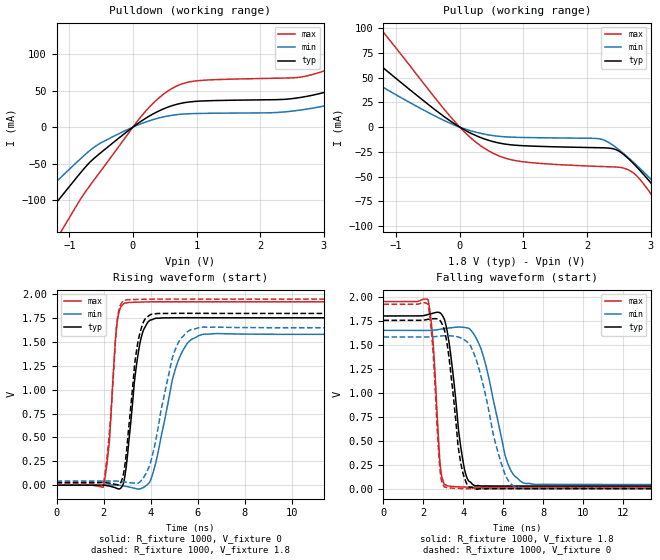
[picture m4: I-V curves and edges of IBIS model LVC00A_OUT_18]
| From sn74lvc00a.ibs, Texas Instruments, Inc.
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[Model]   LVC00A_OUT_18
Model_type  Output
Vref =   0
Rref =   1000
Cref =   30p
Vmeas =   0.9
| variable   typ   min   max
C_comp   6.70pF   4.46pF   9.98pF
| C_pullup   5.89pF   4.46pF   6.78pF
| C_pulldown   7.50pF   4.66pF   9.98pF
[Temperature Range]   40   100   -40
| Ambient temperature   25   85   -40
[Voltage range]   1.8   1.65   1.95
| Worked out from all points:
|   slope of the pulldown table from 0 to 0.27 V, typ, clamps not added: 17.1 ohm
|   slope of the pullup table from 0 to 0.27 V, typ, clamps not added: 29.9 ohm
|   rising waveform, R_fixture 1000, V_fixture 0: 20-80 % time 453ps typ, 823ps min, 292ps max; typ from 0 V to 1.75 V
|   falling waveform, R_fixture 1000, V_fixture 1.8: 20-80 % time 574ps typ, 1ns min, 320ps max; typ from 1.8 V to 0.027 V
|   rising waveform, R_fixture 1000, V_fixture 1.8: 20-80 % time 437ps typ, 793ps min, 326ps max; typ from 0.027 V to 1.8 V
|   falling waveform, R_fixture 1000, V_fixture 0: 20-80 % time 545ps typ, 1.06ns min, 321ps max; typ from 1.75 V to 0 V
[Pulldown]
| LVC00A_OUT_18
|   Voltage   I(typ)   I(min)   I(max)
-5.5V     -559.1mA   -452.2mA   -710.9mA
-2.18V    -208.5mA   -158.8mA   -285.4mA
-1.865V   -175.2mA   -131.6mA   -244.5mA
-1.48V    -133.9mA   -98.56mA   -193.1mA
-1.07V    -89.31mA   -63.76mA   -134.9mA
70mV      4.491mA    2.617mA    8.125mA
615mV     29.45mA    16.27mA    53.12mA
2.815V    43.69mA    25.92mA    72.1mA
4.325V    93.52mA    64.21mA    142.7mA
5.155V    134.5mA    96.03mA    199.6mA
6.155V    191.3mA    141.3mA    276.1mA
11V       510.2mA    405.2mA    689.3mA
[Pullup]
| LVC00A_OUT_18
|   Voltage   I(typ)   I(min)   I(max)
-5.5V     324.9mA    249.5mA    454.8mA
-2.68V    143.9mA    103mA      216.3mA
-2.015V   104.9mA    73.15mA    161.8mA
-1.32V    66.21mA    44.72mA    105.6mA
360mV     -11.3mA    -6.711mA   -20.18mA
985mV     -18.72mA   -10.42mA   -34.9mA
2.465V    -23.02mA   -20.97mA   -40.36mA
2.785V    -40.46mA   -38.76mA   -49.43mA
3.365V    -85.63mA   -77.45mA   -103.2mA
3.56V     -102.6mA   -91.66mA   -124.4mA
3.775V    -122mA     -107.8mA   -148.7mA
11V       -874.4mA   -739.7mA   -1.068A
[Ramp]
| LVC00A_OUT_18
| variable   typ   min   max
dV/dt_r   1.08/4.91E-10   0.98/9.40E-10   1.17/3.09E-10
dV/dt_f   1.09/6.33E-10   0.99/1.06E-09   1.17/3.42E-10
R_load = 1000
[Rising Waveform]
| LVC00A_OUT_18
R_fixture =   1000
C_fixture =   0
L_fixture =   0
V_fixture =   0
V_fixture_min = 0
V_fixture_max = 0
|   Time   V(typ)   V(min)   V(max)
0s        194.2pV    4.892nV    16.26pV
1.985ns   404.1uV    373.2uV    -23.31mV
2.245ns   -10.16mV   471.7uV    459mV
2.56ns    -33.94mV   44.5uV     1.676V
2.9ns     90mV       -10.62mV   1.908V
3.535ns   1.478V     -39.68mV   1.919V
4.17ns    1.746V     191.2mV    1.922V
5.135ns   1.755V     1.282V     1.922V
6.165ns   1.755V     1.578V     1.922V
24.99ns   1.754V     1.581V     1.922V
[Falling Waveform]
| LVC00A_OUT_18
R_fixture =   1000
C_fixture =   0
L_fixture =   0
V_fixture =   1.8
V_fixture_min = 1.65
V_fixture_max = 1.95
|   Time   V(typ)   V(min)   V(max)
0s        1.8V       1.65V      1.95V
2.235ns   1.815V     1.649V     1.971V
2.5ns     1.83V      1.652V     1.496V
2.855ns   1.829V     1.662V     230.4mV
3.195ns   1.642V     1.672V     29.1mV
4.015ns   254.5mV    1.682V     16.78mV
4.57ns    30.96mV    1.598V     15.72mV
6.16ns    26.88mV    304.4mV    16.2mV
7.04ns    26.92mV    57.73mV    16.27mV
24.99ns   27.13mV    42.42mV    16.27mV
[Rising Waveform]
| LVC00A_OUT_18
R_fixture =   1000
C_fixture =   0
L_fixture =   0
V_fixture =   1.8
V_fixture_min = 1.65
V_fixture_max = 1.95
|   Time   V(typ)   V(min)   V(max)
0s        27.13mV    42.42mV    16.27mV
1.985ns   27.38mV    42.65mV    1.041mV
2.245ns   20.32mV    42.65mV    552.1mV
2.57ns    4.142mV    41.94mV    1.711V
2.865ns   146.7mV    33.96mV    1.935V
3.44ns    1.475V     20.59mV    1.947V
4.015ns   1.79V      257.5mV    1.95V
4.93ns    1.8V       1.341V     1.95V
5.75ns    1.801V     1.634V     1.95V
24.99ns   1.8V       1.65V      1.95V
[Falling Waveform]
| LVC00A_OUT_18
R_fixture =   1000
C_fixture =   0
L_fixture =   0
V_fixture =   0
V_fixture_min = 0
V_fixture_max = 0
|   Time   V(typ)   V(min)   V(max)
0s        1.754V     1.581V     1.922V
2.23ns    1.765V     1.581V     1.925V
2.485ns   1.771V     1.583V     1.431V
2.825ns   1.755V     1.59V      215.7mV
3.08ns    1.633V     1.594V     14.71mV
3.82ns    335.6mV    1.576V     1.331mV
4.325ns   13.62mV    1.503V     -430.2uV
5.895ns   -394.3uV   271.1mV    -108.1uV
6.56ns    -309.8uV   24.28mV    -20.93uV
24.99ns   18nV       -22.72nV   4.169nV
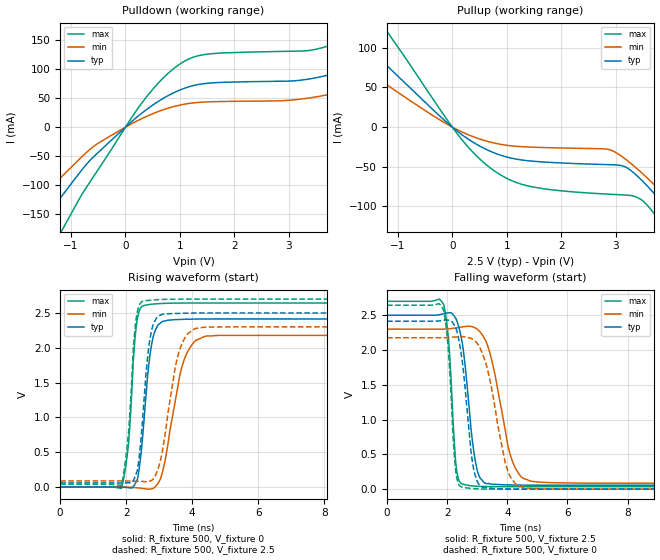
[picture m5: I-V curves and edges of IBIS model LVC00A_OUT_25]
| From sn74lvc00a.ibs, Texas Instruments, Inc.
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[Model]   LVC00A_OUT_25
Model_type  Output
Vref =   0
Rref =   500
Cref =   30p
Vmeas =   1.25
| variable   typ   min   max
C_comp   6.42pF   4.39pF   9.02pF
| C_pullup   5.82pF   4.40pF   6.92pF
| C_pulldown   7.02pF   4.39pF   9.02pF
[Temperature Range]   40   100   -40
| Ambient temperature   25   85   -40
[Voltage range]   2.5   2.3   2.7
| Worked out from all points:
|   slope of the pulldown table from 0 to 0.375 V, typ, clamps not added: 12.7 ohm
|   slope of the pullup table from 0 to 0.375 V, typ, clamps not added: 20 ohm
|   rising waveform, R_fixture 500, V_fixture 0: 20-80 % time 281ps typ, 499ps min, 214ps max; typ from 0 V to 2.41 V
|   falling waveform, R_fixture 500, V_fixture 2.5: 20-80 % time 352ps typ, 596ps min, 212ps max; typ from 2.5 V to 0.057 V
|   rising waveform, R_fixture 500, V_fixture 2.5: 20-80 % time 264ps typ, 451ps min, 221ps max; typ from 0.057 V to 2.5 V
|   falling waveform, R_fixture 500, V_fixture 0: 20-80 % time 338ps typ, 578ps min, 214ps max; typ from 2.41 V to 0 V
[Pulldown]
| LVC00A_OUT_25
|   Voltage   I(typ)   I(min)   I(max)
-5.5V     -598.1mA   -479.8mA   -766.5mA
-2.12V    -233mA     -174.4mA   -327.1mA
-1.575V   -168.1mA   -123.2mA   -244.7mA
-1.15V    -116.2mA   -83.21mA   -174.9mA
-565mV    -49.19mA   -31.72mA   -81.94mA
365mV     28.75mA    17.58mA    49.46mA
1.32V     73.05mA    42.4mA     122.5mA
4V        96.78mA    61.72mA    149.2mA
4.6V      117.3mA    77.78mA    177.9mA
5.77V     171.8mA    120.4mA    253.2mA
7.055V    245.3mA    179.5mA    351.5mA
11V       504.9mA    394.6mA    686.5mA
[Pullup]
| LVC00A_OUT_25
|   Voltage   I(typ)   I(min)   I(max)
-5.5V     363.4mA    279.9mA    508.8mA
-2.6V     169.4mA    122.6mA    251.6mA
-1.815V   117.7mA    83.03mA    179.1mA
-1.37V    88.47mA    61.37mA    136.9mA
170mV     -9.222mA   -5.867mA   -15.32mA
760mV     -32.2mA    -19.89mA   -54.58mA
2.905V    -47.35mA   -28.79mA   -84.65mA
3.45V     -65.04mA   -55.88mA   -90.57mA
3.92V     -100.7mA   -87.07mA   -129.3mA
4.19V     -123.8mA   -106.6mA   -157.6mA
4.495V    -151.4mA   -129.7mA   -191.8mA
11V       -830.2mA   -699.2mA   -1.022A
[Ramp]
| LVC00A_OUT_25
| variable   typ   min   max
dV/dt_r   1.46/3.04E-10   1.33/5.65E-10   1.60/2.29E-10
dV/dt_f   1.49/3.73E-10   1.35/6.69E-10   1.62/2.16E-10
R_load = 500
[Rising Waveform]
| LVC00A_OUT_25
R_fixture =   500
C_fixture =   0
L_fixture =   0
V_fixture =   0
V_fixture_min = 0
V_fixture_max = 0
|   Time   V(typ)   V(min)   V(max)
0s        177.7pV    3.876nV    17.91pV
1.86ns    -4.644mV   420.6uV    -18.27mV
2.07ns    -12.01mV   -4.351mV   607.9mV
2.31ns    77.31mV    -12.76mV   2.325V
2.565ns   1.105V     -27.02mV   2.611V
2.735ns   1.942V     -31.22mV   2.624V
2.955ns   2.32V      45.54mV    2.634V
3.74ns    2.409V     1.803V     2.644V
4.415ns   2.414V     2.167V     2.644V
24.99ns   2.414V     2.176V     2.644V
[Falling Waveform]
| LVC00A_OUT_25
R_fixture =   500
C_fixture =   0
L_fixture =   0
V_fixture =   2.5
V_fixture_min = 2.3
V_fixture_max = 2.7
|   Time   V(typ)   V(min)   V(max)
0s        2.5V       2.3V       2.7V
1.885ns   2.522V     2.3V       2.653V
2.045ns   2.534V     2.304V     2.15V
2.29ns    2.45V      2.318V     362.8mV
2.485ns   2.144V     2.331V     75.15mV
2.925ns   432mV      2.319V     43.1mV
3.295ns   78.72mV    2.121V     36.91mV
4.135ns   59.94mV    443.1mV    35.46mV
4.8ns     56.84mV    112.3mV    35.69mV
24.99ns   57.33mV    84.96mV    35.94mV
[Rising Waveform]
| LVC00A_OUT_25
R_fixture =   500
C_fixture =   0
L_fixture =   0
V_fixture =   2.5
V_fixture_min = 2.3
V_fixture_max = 2.7
|   Time   V(typ)   V(min)   V(max)
0s        57.33mV    84.96mV    35.94mV
1.86ns    55.23mV    85.11mV    25.69mV
2.07ns    58.68mV    83.49mV    775.4mV
2.285ns   164.7mV    80.98mV    2.351V
2.52ns    1.116V     76.78mV    2.671V
2.68ns    1.995V     77.43mV    2.682V
2.855ns   2.375V     135.2mV    2.689V
3.585ns   2.494V     1.915V     2.699V
4.135ns   2.499V     2.281V     2.7V
24.99ns   2.5V       2.3V       2.7V
[Falling Waveform]
| LVC00A_OUT_25
R_fixture =   500
C_fixture =   0
L_fixture =   0
V_fixture =   0
V_fixture_min = 0
V_fixture_max = 0
|   Time   V(typ)   V(min)   V(max)
0s        2.414V     2.176V     2.644V
1.88ns    2.427V     2.177V     2.576V
2.04ns    2.429V     2.179V     1.998V
2.27ns    2.328V     2.187V     318.5mV
2.48ns    1.907V     2.189V     29.54mV
2.805ns   498mV      2.165V     9.211mV
3.015ns   97.19mV    2.087V     3.614mV
3.985ns   2.007mV    301.9mV    -507.5uV
4.565ns   -464.3uV   19.81mV    -311.5uV
24.99ns   -7.246nV   27.16nV    2.294nV
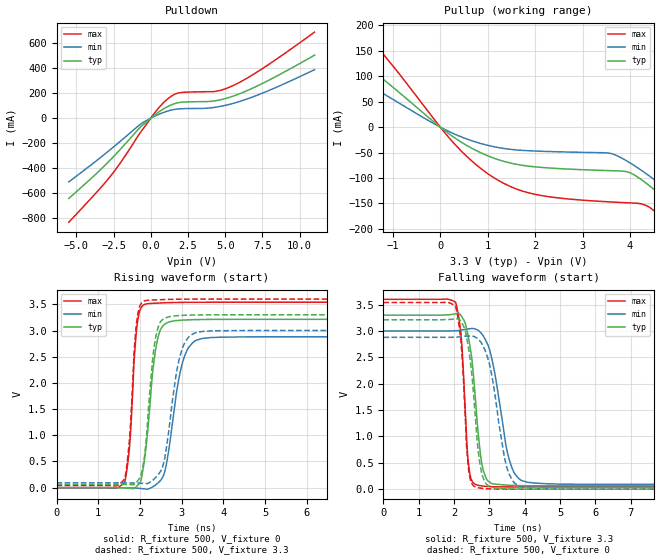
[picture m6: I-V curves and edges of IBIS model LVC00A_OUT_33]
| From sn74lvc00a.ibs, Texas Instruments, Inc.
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[Model]   LVC00A_OUT_33
Model_type  Output
Vref =   0
Rref =   500
Cref =   50p
Vmeas =   1.5
| variable   typ   min   max
C_comp   6.09pF   3.46pF   8.37pF
| C_pullup   5.72pF   3.46pF   7.15pF
| C_pulldown   6.47pF   4.19pF   8.37pF
[Temperature Range]   40   100   -40
| Ambient temperature   25   85   -40
[Voltage range]   3.3   3   3.6
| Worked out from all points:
|   slope of the pulldown table from 0 to 0.495 V, typ, clamps not added: 10.7 ohm
|   slope of the pullup table from 0 to 0.495 V, typ, clamps not added: 15.2 ohm
|   rising waveform, R_fixture 500, V_fixture 0: 20-80 % time 238ps typ, 331ps min, 155ps max; typ from 0 V to 3.21 V
|   falling waveform, R_fixture 500, V_fixture 3.3: 20-80 % time 274ps typ, 431ps min, 169ps max; typ from 3.3 V to 0.065 V
|   rising waveform, R_fixture 500, V_fixture 3.3: 20-80 % time 209ps typ, 313ps min, 159ps max; typ from 0.065 V to 3.3 V
|   falling waveform, R_fixture 500, V_fixture 0: 20-80 % time 268ps typ, 410ps min, 175ps max; typ from 3.21 V to 0 V
[Pulldown]
| LVC00A_OUT_33
|   Voltage   I(typ)   I(min)   I(max)
-5.5V     -642.1mA   -509.2mA   -832.1mA
-3.645V   -442.6mA   -340.3mA   -594.1mA
-2.71V    -333.2mA   -250.5mA   -464.6mA
-1.885V   -228.4mA   -168.1mA   -330.7mA
-620mV    -62.4mA    -41.49mA   -102.1mA
455mV     42.83mA    26.93mA    71.74mA
1.215V    98.07mA    60.46mA    162.3mA
1.91V     125.9mA    75.23mA    203.5mA
4.31V     139.6mA    87.57mA    214.6mA
5.45V     173.8mA    116.3mA    257.3mA
7.53V     280.4mA    202.4mA    399.9mA
11V       505.3mA    389mA      689.8mA
[Pullup]
| LVC00A_OUT_33
|   Voltage   I(typ)   I(min)   I(max)
-5.5V     404.4mA    310.8mA    569.2mA
-3.515V   265mA      197.3mA    383.4mA
-2.48V    190.1mA    138.3mA    280.1mA
-1.635V   127.1mA    90.28mA    191.1mA
505mV     -33.05mA   -21.44mA   -52.79mA
1.855V    -76.61mA   -46.34mA   -128.9mA
3.7V      -85.85mA   -55.1mA    -147.6mA
4.24V     -103.3mA   -84.95mA   -151mA
4.895V    -154.7mA   -130.6mA   -201.2mA
5.365V    -197.4mA   -166.8mA   -253mA
5.825V    -241.6mA   -203.9mA   -307.6mA
11V       -786.6mA   -661.2mA   -974mA
[Ramp]
| LVC00A_OUT_33
| variable   typ   min   max
dV/dt_r   1.94/2.61E-10   1.75/3.40E-10   2.13/1.59E-10
dV/dt_f   1.97/2.96E-10   1.77/4.74E-10   2.14/1.74E-10
R_load = 500
[Rising Waveform]
| LVC00A_OUT_33
R_fixture =   500
C_fixture =   0
L_fixture =   0
V_fixture =   0
V_fixture_min = 0
V_fixture_max = 0
|   Time   V(typ)   V(min)   V(max)
0s        184.9pV    3.596nV    20.95pV
1.64ns    -7.05mV    -2.78mV    116.5mV
1.75ns    -12.34mV   -3.999mV   776.5mV
1.935ns   36.01mV    -9.967mV   3.129V
2.185ns   1.081V     -27.57mV   3.511V
2.335ns   2.411V     30.35mV    3.52V
2.495ns   3.02V      139mV      3.526V
3.03ns    3.2V       2.416V     3.537V
3.505ns   3.21V      2.85V      3.539V
24.99ns   3.212V     2.88V      3.539V
[Falling Waveform]
| LVC00A_OUT_33
R_fixture =   500
C_fixture =   0
L_fixture =   0
V_fixture =   3.3
V_fixture_min = 3
V_fixture_max = 3.6
|   Time   V(typ)   V(min)   V(max)
0s        3.3V       3V         3.6V
2.045ns   3.327V     3.003V     3.541V
2.195ns   3.293V     3.015V     2.962V
2.415ns   2.847V     3.039V     434.4mV
2.695ns   976.4mV    3.004V     70.43mV
2.805ns   416.9mV    2.926V     58.84mV
2.955ns   155.1mV    2.737V     50.05mV
3.565ns   73.19mV    550.6mV    41.99mV
4.075ns   64.93mV    129.6mV    41.64mV
24.99ns   64.52mV    92.1mV     41.93mV
[Rising Waveform]
| LVC00A_OUT_33
R_fixture =   500
C_fixture =   0
L_fixture =   0
V_fixture =   3.3
V_fixture_min = 3
V_fixture_max = 3.6
|   Time   V(typ)   V(min)   V(max)
0s        64.52mV    92.1mV     41.93mV
1.64ns    60.18mV    90.6mV     174.6mV
1.75ns    57.97mV    89.94mV    939.1mV
1.915ns   101.8mV    87.46mV    3.123V
2.125ns   708.7mV    79.35mV    3.57V
2.31ns    2.499V     145mV      3.583V
2.46ns    3.119V     273.8mV    3.588V
2.99ns    3.287V     2.595V     3.598V
3.485ns   3.298V     2.981V     3.6V
24.99ns   3.3V       3V         3.6V
[Falling Waveform]
| LVC00A_OUT_33
R_fixture =   500
C_fixture =   0
L_fixture =   0
V_fixture =   0
V_fixture_min = 0
V_fixture_max = 0
|   Time   V(typ)   V(min)   V(max)
0s        3.212V     2.88V      3.539V
2.04ns    3.229V     2.882V     3.472V
2.195ns   3.181V     2.891V     2.806V
2.35ns    2.902V     2.902V     848.4mV
2.415ns   2.642V     2.904V     346.8mV
2.685ns   718.2mV    2.844V     25.65mV
3.01ns    45.5mV     2.345V     5.171mV
3.51ns    6.907mV    377mV      55.4uV
4.005ns   -19.67uV   26.68mV    -327.8uV
24.99ns   8.065nV    30.47nV    3.04nV
